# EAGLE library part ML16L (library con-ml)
HARTING

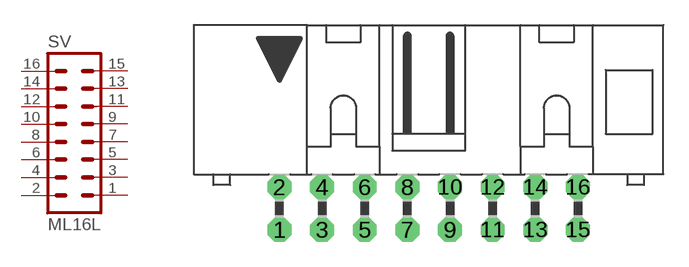
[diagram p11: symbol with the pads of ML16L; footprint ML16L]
Designator prefix SV

## ML16L (OC_FARNELL: unknown; OC_NEWARK: unknown)  [ML16L]
1  1  pas
2  2  pas
3  3  pas
4  4  pas
5  5  pas
6  6  pas
7  7  pas
8  8  pas
9  9  pas
10  10  pas
11  11  pas
12  12  pas
13  13  pas
14  14  pas
15  15  pas
16  16  pas

## Footprint ML16L (pad centres in mm)
HARTING
drill 0.914 octagon: 1 -8.89,-1.27; 2 -8.89,1.27; 3 -6.35,-1.27; 4 -6.35,1.27; 5 -3.81,-1.27; 6 -3.81,1.27; 7 -1.27,-1.27; 8 -1.27,1.27; 9 1.27,-1.27; 10 1.27,1.27; 11 3.81,-1.27; 12 3.81,1.27; 13 6.35,-1.27; 14 6.35,1.27; 15 8.89,-1.27; 16 8.89,1.27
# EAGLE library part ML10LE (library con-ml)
HARTING

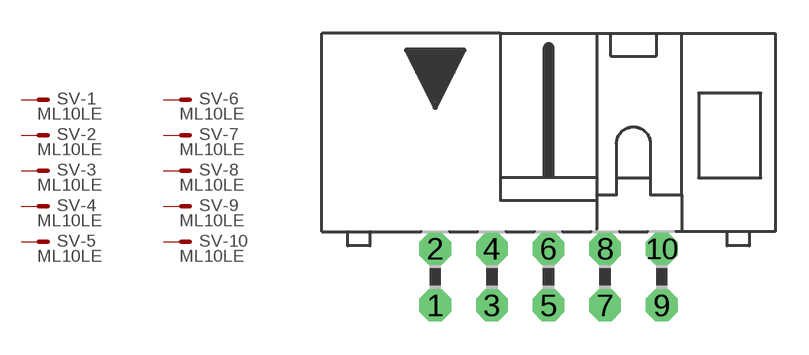
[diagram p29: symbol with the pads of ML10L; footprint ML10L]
Designator prefix SV; gates -1=M -2=M -3=M -4=M -5=M -6=M -7=M -8=M -9=M -10=M

## ML10LE (OC_FARNELL: unknown; OC_NEWARK: unknown)  [ML10L]
1  -1:S  pas
2  -2:S  pas
3  -3:S  pas
4  -4:S  pas
5  -5:S  pas
6  -6:S  pas
7  -7:S  pas
8  -8:S  pas
9  -9:S  pas
10  -10:S  pas

## Footprint ML10L (pad centres in mm)
HARTING
drill 0.914 octagon: 1 -5.08,-1.27; 2 -5.08,1.27; 3 -2.54,-1.27; 4 -2.54,1.27; 5 0,-1.27; 6 0,1.27; 7 2.54,-1.27; 8 2.54,1.27; 9 5.08,-1.27; 10 5.08,1.27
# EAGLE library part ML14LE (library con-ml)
HARTING

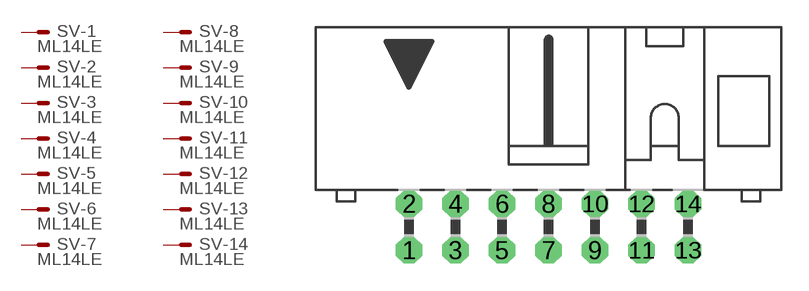
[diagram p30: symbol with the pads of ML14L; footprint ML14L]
Designator prefix SV; gates -1=M -2=M -3=M -4=M -5=M -6=M -7=M -8=M -9=M -10=M -11=M -12=M -13=M -14=M

## ML14LE (OC_FARNELL: unknown; OC_NEWARK: unknown)  [ML14L]
1  -1:S  pas
2  -2:S  pas
3  -3:S  pas
4  -4:S  pas
5  -5:S  pas
6  -6:S  pas
7  -7:S  pas
8  -8:S  pas
9  -9:S  pas
10  -10:S  pas
11  -11:S  pas
12  -12:S  pas
13  -13:S  pas
14  -14:S  pas

## Footprint ML14L (pad centres in mm)
HARTING
drill 0.914 octagon: 1 -7.62,-1.27; 2 -7.62,1.27; 3 -5.08,-1.27; 4 -5.08,1.27; 5 -2.54,-1.27; 6 -2.54,1.27; 7 0,-1.27; 8 0,1.27; 9 2.54,-1.27; 10 2.54,1.27; 11 5.08,-1.27; 12 5.08,1.27; 13 7.62,-1.27; 14 7.62,1.27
